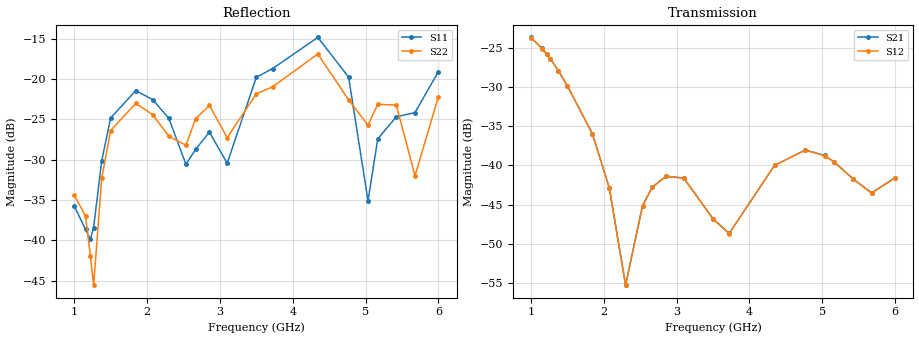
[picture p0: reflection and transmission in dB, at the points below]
!Agilent Technologies,E8364B,MY43040528,A.07.50.67
!Agilent E8364B: A.07.50.67
!Date: Sunday, March 01, 2026 21:11:22
!Correction: S11(Full 2 Port(1,2))
!S21(Full 2 Port(1,2))
!S12(Full 2 Port(1,2))
!S22(Full 2 Port(1,2))
!S2P File: Measurements: S11, S21, S12, S22:
# Hz S  dB  R 50
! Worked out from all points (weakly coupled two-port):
!   451 points, 1 GHz to 6 GHz, reference 50 ohm
!   highest |S21| = -23.66 dB at 1 GHz (marker M1); lowest = -55.3 dB at 2.3 GHz (marker M2)
!   lowest |S11| = -39.9 dB at 1.222 GHz (marker M3), VSWR 1.02, Z = 49.5 + j0.896 ohm
!   |S11| at or under -10 dB: start of sweep to end of sweep
!   |S22| runs from -45.6 to -16.6 dB; largest |S21 - S12| = 0.00025
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1e9  -35.74 58.3  -23.66 148.6  -23.70 148.7  -34.39 15.8
1.155556e9  -38.66 92.4  -25.07 58.7  -25.10 58.7  -36.99 17.8
1.222222e9  -39.86 117.2  -25.81 20.2  -25.84 20.2  -41.97 27.5
1.266667e9  -38.42 145.9  -26.36 -5.3  -26.39 -5.3  -45.56 76.4
1.377778e9  -30.14 161.9  -27.91 -68.3  -27.94 -68.2  -32.33 107.6
1.5e9  -24.84 141.8  -29.81 -135.7  -29.83 -135.7  -26.40 78.9
1.844444e9  -21.45 81.7  -35.94 37.7  -35.97 37.8  -23.03 -0.1
2.077778e9  -22.56 53.1  -42.88 -85.2  -42.93 -85.2  -24.43 -36.2
2.3e9  -24.90 30.4  -55.26 -132.1  -55.24 -132.2  -27.11 -60.4
2.533333e9  -30.58 36.4  -45.11 165.9  -45.14 165.9  -28.22 -48.5
2.666667e9  -28.74 56.2  -42.75 96.0  -42.78 96.1  -24.93 -55.9
2.855556e9  -26.59 42.1  -41.36 -5.7  -41.40 -5.7  -23.29 -89.9
3.1e9  -30.45 57.6  -41.61 -138.5  -41.65 -138.6  -27.28 -113.1
3.5e9  -19.80 47.2  -46.79 22.5  -46.82 22.7  -21.85 -124.7
3.722222e9  -18.72 26.7  -48.67 -53.1  -48.68 -53.3  -20.98 -146.3
4.344444e9  -14.85 -44.4  -39.98 12.8  -40.00 12.7  -16.91 113.4
4.766667e9  -19.78 -110.0  -38.02 132.7  -38.05 132.8  -22.60 37.6
5.033333e9  -35.11 -86.5  -38.72 -25.9  -38.76 -25.9  -25.74 43.7
5.166667e9  -27.43 -42.3  -39.56 -106.9  -39.60 -106.9  -23.14 30.9
5.422222e9  -24.69 -66.6  -41.70 90.2  -41.74 90.2  -23.25 -23.6
5.677778e9  -24.17 -51.3  -43.49 -90.4  -43.54 -90.4  -32.01 -24.0
6e9  -19.09 -70.1  -41.55 41.2  -41.58 41.2  -22.19 -23.3
